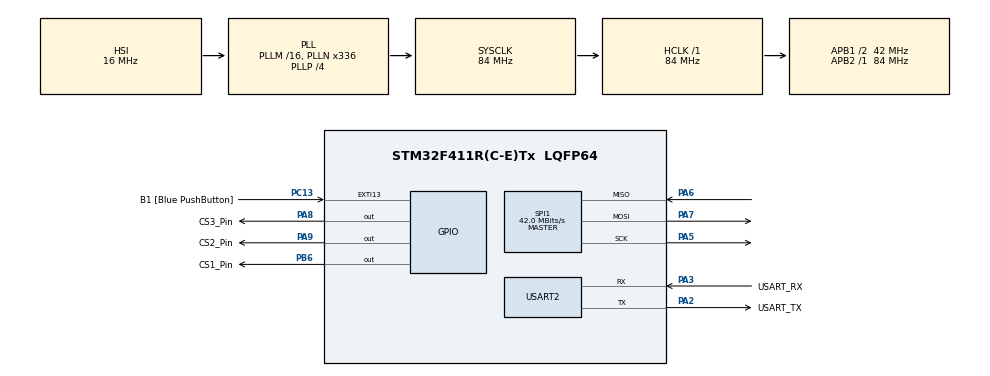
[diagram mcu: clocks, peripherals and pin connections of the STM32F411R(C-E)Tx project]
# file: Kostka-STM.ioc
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Mcu.Family=STM32F4
Mcu.Name=STM32F411R(C-E)Tx
Mcu.Package=LQFP64
NVIC.PriorityGroup=NVIC_PRIORITYGROUP_0
PA13.GPIO_Label=TMS
PA13.Mode=Serial_Wire
PA13.Signal=SYS_JTMS-SWDIO
PA14.GPIO_Label=TCK
PA14.Mode=Serial_Wire
PA14.Signal=SYS_JTCK-SWCLK
PA2.GPIO_Label=USART_TX
PA2.Mode=Asynchronous
PA2.Signal=USART2_TX
PA3.GPIO_Label=USART_RX
PA3.Mode=Asynchronous
PA3.Signal=USART2_RX
PA5.Mode=Full_Duplex_Master
PA5.Signal=SPI1_SCK
PA6.Mode=Full_Duplex_Master
PA6.Signal=SPI1_MISO
PA7.Mode=Full_Duplex_Master
PA7.Signal=SPI1_MOSI
PA8.GPIO_Label=CS3_Pin
PA8.PinState=GPIO_PIN_SET
PA8.Signal=GPIO_Output
PA9.GPIO_Label=CS2_Pin
PA9.PinState=GPIO_PIN_SET
PA9.Signal=GPIO_Output
PB3.GPIO_Label=SWO
PB3.Signal=SYS_JTDO-SWO
PB6.GPIO_Label=CS1_Pin
PB6.PinState=GPIO_PIN_SET
PB6.Signal=GPIO_Output
PC13-ANTI_TAMP.GPIO_Label=B1 [Blue PushButton]
PC13-ANTI_TAMP.GPIO_ModeDefaultEXTI=GPIO_MODE_IT_FALLING
PC13-ANTI_TAMP.Signal=GPXTI13
PC14-OSC32_IN.Mode=LSE-External-Oscillator
PC14-OSC32_IN.Signal=RCC_OSC32_IN
PC15-OSC32_OUT.Mode=LSE-External-Oscillator
PC15-OSC32_OUT.Signal=RCC_OSC32_OUT
PH0\ -\ OSC_IN.Mode=HSE-External-Clock-Source
PH0\ -\ OSC_IN.Signal=RCC_OSC_IN
PH1\ -\ OSC_OUT.Mode=HSE-External-Clock-Source
PH1\ -\ OSC_OUT.Signal=RCC_OSC_OUT
ProjectManager.HeapSize=0x200
ProjectManager.StackSize=0x400
ProjectManager.TargetToolchain=CMake
RCC.48MHZClocksFreq_Value=84000000
RCC.AHBFreq_Value=84000000
RCC.APB1CLKDivider=RCC_HCLK_DIV2
RCC.APB1Freq_Value=42000000
RCC.APB1TimFreq_Value=84000000
RCC.APB2Freq_Value=84000000
RCC.APB2TimFreq_Value=84000000
RCC.CortexFreq_Value=84000000
RCC.FLatency-AdvancedSettings=FLASH_LATENCY_2
RCC.HCLKFreq_Value=84000000
RCC.HSE_VALUE=8000000
RCC.HSI_VALUE=16000000
RCC.PLLN=336
RCC.PLLP=RCC_PLLP_DIV4
RCC.SYSCLKFreq_VALUE=84000000
RCC.SYSCLKSource=RCC_SYSCLKSOURCE_PLLCLK
RCC.VCOOutputFreq_Value=336000000
SPI1.CalculateBaudRate=42.0 MBits/s
SPI1.Direction=SPI_DIRECTION_2LINES
SPI1.Mode=SPI_MODE_MASTER
SPI1.VirtualType=VM_MASTER
USART2.VirtualMode=VM_ASYNC
board=NUCLEO-F411RE

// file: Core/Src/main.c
/* USER CODE BEGIN Header */
/**
  ******************************************************************************
  * @file           : main.c
  * @brief          : Main program body
  ******************************************************************************
  * @attention
  *
  * Copyright (c) 2026 STMicroelectronics.
  * All rights reserved.
  *
  * This software is licensed under terms that can be found in the LICENSE file
  * in the root directory of this software component.
  * If no LICENSE file comes with this software, it is provided AS-IS.
  *
  ******************************************************************************
  */
/* USER CODE END Header */
#include "main.h"

/* USER CODE BEGIN Includes */
#include "app.h"
/* USER CODE END Includes */

SPI_HandleTypeDef hspi1;

UART_HandleTypeDef huart2;

void SystemClock_Config(void);
static void MX_GPIO_Init(void);
static void MX_USART2_UART_Init(void);
static void MX_SPI1_Init(void);

int main(void)
{

  /* MCU Configuration--------------------------------------------------------*/

  /* Reset of all peripherals, Initializes the Flash interface and the Systick. */
  HAL_Init();

  /* Configure the system clock */
  SystemClock_Config();

  /* Initialize all configured peripherals */
  MX_GPIO_Init();
  MX_USART2_UART_Init();
  MX_SPI1_Init();
  /* USER CODE BEGIN 2 */
  cpp_main();
  /* USER CODE END 2 */

  /* Infinite loop */
  while (1)
  {

  }
}

void SystemClock_Config(void)
{
  RCC_OscInitTypeDef RCC_OscInitStruct = {0};
  RCC_ClkInitTypeDef RCC_ClkInitStruct = {0};

  /** Configure the main internal regulator output voltage
  */
  __HAL_RCC_PWR_CLK_ENABLE();
  __HAL_PWR_VOLTAGESCALING_CONFIG(PWR_REGULATOR_VOLTAGE_SCALE1);

  /** Initializes the RCC Oscillators according to the specified parameters
  * in the RCC_OscInitTypeDef structure.
  */
  RCC_OscInitStruct.OscillatorType = RCC_OSCILLATORTYPE_HSI;
  RCC_OscInitStruct.HSIState = RCC_HSI_ON;
  RCC_OscInitStruct.HSICalibrationValue = RCC_HSICALIBRATION_DEFAULT;
  RCC_OscInitStruct.PLL.PLLState = RCC_PLL_ON;
  RCC_OscInitStruct.PLL.PLLSource = RCC_PLLSOURCE_HSI;
  RCC_OscInitStruct.PLL.PLLM = 16;
  RCC_OscInitStruct.PLL.PLLN = 336;
  RCC_OscInitStruct.PLL.PLLP = RCC_PLLP_DIV4;
  RCC_OscInitStruct.PLL.PLLQ = 4;
  if (HAL_RCC_OscConfig(&RCC_OscInitStruct) != HAL_OK)
  {
    Error_Handler();
  }

  /** Initializes the CPU, AHB and APB buses clocks
  */
  RCC_ClkInitStruct.ClockType = RCC_CLOCKTYPE_HCLK|RCC_CLOCKTYPE_SYSCLK
                              |RCC_CLOCKTYPE_PCLK1|RCC_CLOCKTYPE_PCLK2;
  RCC_ClkInitStruct.SYSCLKSource = RCC_SYSCLKSOURCE_PLLCLK;
  RCC_ClkInitStruct.AHBCLKDivider = RCC_SYSCLK_DIV1;
  RCC_ClkInitStruct.APB1CLKDivider = RCC_HCLK_DIV2;
  RCC_ClkInitStruct.APB2CLKDivider = RCC_HCLK_DIV1;

  if (HAL_RCC_ClockConfig(&RCC_ClkInitStruct, FLASH_LATENCY_2) != HAL_OK)
  {
    Error_Handler();
  }
}

static void MX_SPI1_Init(void)
{

  /* SPI1 parameter configuration*/
  hspi1.Instance = SPI1;
  hspi1.Init.Mode = SPI_MODE_MASTER;
  hspi1.Init.Direction = SPI_DIRECTION_2LINES;
  hspi1.Init.DataSize = SPI_DATASIZE_8BIT;
  hspi1.Init.CLKPolarity = SPI_POLARITY_LOW;
  hspi1.Init.CLKPhase = SPI_PHASE_1EDGE;
  hspi1.Init.NSS = SPI_NSS_SOFT;
  hspi1.Init.BaudRatePrescaler = SPI_BAUDRATEPRESCALER_2;
  hspi1.Init.FirstBit = SPI_FIRSTBIT_MSB;
  hspi1.Init.TIMode = SPI_TIMODE_DISABLE;
  hspi1.Init.CRCCalculation = SPI_CRCCALCULATION_DISABLE;
  hspi1.Init.CRCPolynomial = 10;
  if (HAL_SPI_Init(&hspi1) != HAL_OK)
  {
    Error_Handler();
  }

}

static void MX_USART2_UART_Init(void)
{

  huart2.Instance = USART2;
  huart2.Init.BaudRate = 115200;
  huart2.Init.WordLength = UART_WORDLENGTH_8B;
  huart2.Init.StopBits = UART_STOPBITS_1;
  huart2.Init.Parity = UART_PARITY_NONE;
  huart2.Init.Mode = UART_MODE_TX_RX;
  huart2.Init.HwFlowCtl = UART_HWCONTROL_NONE;
  huart2.Init.OverSampling = UART_OVERSAMPLING_16;
  if (HAL_UART_Init(&huart2) != HAL_OK)
  {
    Error_Handler();
  }

}

static void MX_GPIO_Init(void)
{
  GPIO_InitTypeDef GPIO_InitStruct = {0};

  /* GPIO Ports Clock Enable */
  __HAL_RCC_GPIOC_CLK_ENABLE();
  __HAL_RCC_GPIOH_CLK_ENABLE();
  __HAL_RCC_GPIOA_CLK_ENABLE();
  __HAL_RCC_GPIOB_CLK_ENABLE();

  /*Configure GPIO pin Output Level */
  HAL_GPIO_WritePin(GPIOA, CS3_Pin|CS2_Pin, GPIO_PIN_SET);

  /*Configure GPIO pin Output Level */
  HAL_GPIO_WritePin(CS1_GPIO_Port, CS1_Pin, GPIO_PIN_SET);

  /*Configure GPIO pin : B1_Pin */
  GPIO_InitStruct.Pin = B1_Pin;
  GPIO_InitStruct.Mode = GPIO_MODE_IT_FALLING;
  GPIO_InitStruct.Pull = GPIO_NOPULL;
  HAL_GPIO_Init(B1_GPIO_Port, &GPIO_InitStruct);

  /*Configure GPIO pins : CS3_Pin_Pin CS2_Pin_Pin */
  GPIO_InitStruct.Pin = CS3_Pin|CS2_Pin;
  GPIO_InitStruct.Mode = GPIO_MODE_OUTPUT_PP;
  GPIO_InitStruct.Pull = GPIO_NOPULL;
  GPIO_InitStruct.Speed = GPIO_SPEED_FREQ_LOW;
  HAL_GPIO_Init(GPIOA, &GPIO_InitStruct);

  /*Configure GPIO pin : CS1_Pin_Pin */
  GPIO_InitStruct.Pin = CS1_Pin;
  GPIO_InitStruct.Mode = GPIO_MODE_OUTPUT_PP;
  GPIO_InitStruct.Pull = GPIO_NOPULL;
  GPIO_InitStruct.Speed = GPIO_SPEED_FREQ_LOW;
  HAL_GPIO_Init(CS1_GPIO_Port, &GPIO_InitStruct);

}

void Error_Handler(void)
{
  __disable_irq();
  while (1)
  {
  }
}
